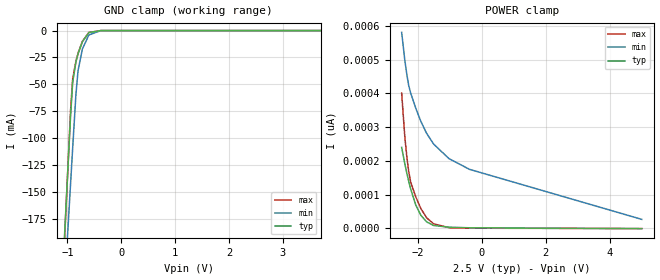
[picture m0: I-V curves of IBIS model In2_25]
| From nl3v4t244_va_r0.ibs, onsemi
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|//////////////////////////////////////////////////////////////////////////////
|//////////////////////////////////////////////////////////////////////////////
[Model]  In2_25
Model_type Input
Vinh =  1.6
Vinl =  0.7
|  variable   typ   min   max
C_comp   4.8pF   4.8pF   4.8pF
|//////////////////////////////////////////////////////////////////////////////
[Temperature Range]   25   125   -40
|//////////////////////////////////////////////////////////////////////////////
[Voltage Range]   2.50V   2.30V   2.70V
|//////////////////////////////////////////////////////////////////////////////
[POWER Clamp Reference] 2.50V   2.30V   2.70V
|//////////////////////////////////////////////////////////////////////////////
[GND Clamp Reference]   0V   0V   0V
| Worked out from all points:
|   GND clamp passes 1 mA (typ) near -0.57 V on its own axis
|//////////////////////////////////////////////////////////////////////////////
[GND Clamp]
|   Voltage   I(typ)   I(min)   I(max)
-2.5V     -1.631A    -1.479A    -1.789A
-1.16V    -298.7mA   -331.6mA   -314.9mA
-1.1V     -239.1mA   -280.2mA   -248.9mA
-1.04V    -179.4mA   -228.8mA   -182.9mA
-940mV    -79.99mA   -143.1mA   -74.63mA
-900mV    -47.98mA   -108.9mA   -44.88mA
-840mV    -29.25mA   -59.37mA   -28.37mA
-800mV    -21.56mA   -37.01mA   -20.87mA
-720mV    -10.43mA   -17.13mA   -10.05mA
-600mV    -1.852mA   -4.106mA   -1.703mA
-380mV    -1.355uA   -20.62uA   -1.03uA
5V        2.095pA    236.7pA    503.4fA
|//////////////////////////////////////////////////////////////////////////////
[POWER Clamp]
|   Voltage   I(typ)   I(min)   I(max)
-2.5V     240pA      581.3pA    401.2pA
-2.4V     190.8pA    497.9pA    269.6pA
-2.34V    164.2pA    457.4pA    213.7pA
-2.28V    139.4pA    423.7pA    168.9pA
-2.22V    116.9pA    401.8pA    137.6pA
-2.06V    69.14pA    356.6pA    93.48pA
-1.9V     38.38pA    317.1pA    58.38pA
-1.72V    18.9pA     281.6pA    31.04pA
-1.5V     8.097pA    249.7pA    13.03pA
-1.02V    3.162pA    206.5pA    1.689pA
-380mV    1.279pA    174.8pA    133.9fA
5V        -1.237pA   26.35pA    -923.7fA
